VERSION 5.8 ;
BUSBITCHARS "[]" ;
DIVIDERCHAR "/" ;
UNITS
    DATABASE MICRONS 1000 ;
END UNITS

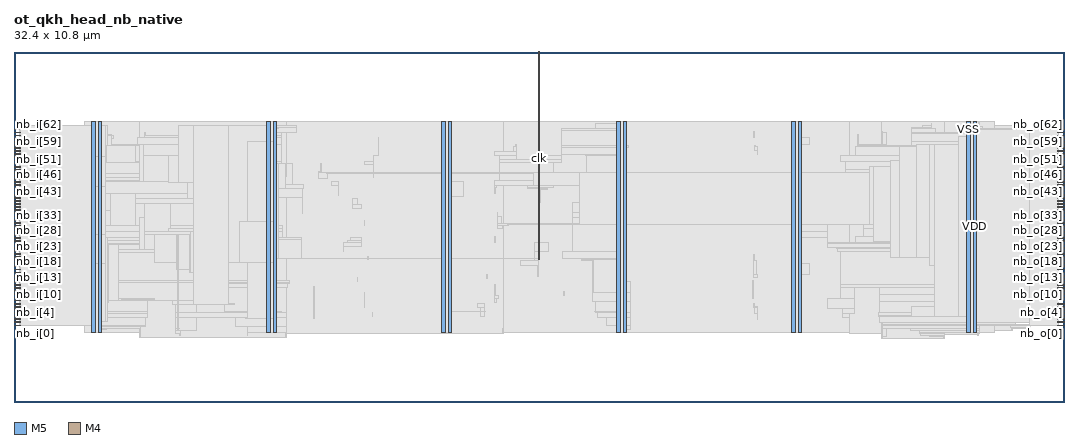
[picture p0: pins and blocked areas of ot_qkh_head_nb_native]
MACRO ot_qkh_head_nb_native
  FOREIGN ot_qkh_head_nb_native 0 0 ;
  CLASS BLOCK ;
  SIZE 32.4 BY 10.8 ;
  PIN clk
    DIRECTION INPUT ;
    USE SIGNAL ;
    PORT
      LAYER M5 ;
        RECT  16.176 10.608 16.2 10.8 ;
    END
    PORT
      LAYER M5 ;
        RECT  16.176 4.405 16.2 10.64 ;
    END
  END clk
  PIN nb_i[0]
    DIRECTION INPUT ;
    USE SIGNAL ;
    PORT
      LAYER M4 ;
        RECT  0 2.352 0.192 2.376 ;
    END
  END nb_i[0]
  PIN nb_i[10]
    DIRECTION INPUT ;
    USE SIGNAL ;
    PORT
      LAYER M4 ;
        RECT  0 3.312 0.192 3.336 ;
    END
  END nb_i[10]
  PIN nb_i[11]
    DIRECTION INPUT ;
    USE SIGNAL ;
    PORT
      LAYER M4 ;
        RECT  0 3.408 0.192 3.432 ;
    END
  END nb_i[11]
  PIN nb_i[12]
    DIRECTION INPUT ;
    USE SIGNAL ;
    PORT
      LAYER M4 ;
        RECT  0 3.504 0.192 3.528 ;
    END
  END nb_i[12]
  PIN nb_i[13]
    DIRECTION INPUT ;
    USE SIGNAL ;
    PORT
      LAYER M4 ;
        RECT  0 3.6 0.192 3.624 ;
    END
  END nb_i[13]
  PIN nb_i[14]
    DIRECTION INPUT ;
    USE SIGNAL ;
    PORT
      LAYER M4 ;
        RECT  0 3.696 0.192 3.72 ;
    END
  END nb_i[14]
  PIN nb_i[15]
    DIRECTION INPUT ;
    USE SIGNAL ;
    PORT
      LAYER M4 ;
        RECT  0 3.792 0.192 3.816 ;
    END
  END nb_i[15]
  PIN nb_i[16]
    DIRECTION INPUT ;
    USE SIGNAL ;
    PORT
      LAYER M4 ;
        RECT  0 3.888 0.192 3.912 ;
    END
  END nb_i[16]
  PIN nb_i[17]
    DIRECTION INPUT ;
    USE SIGNAL ;
    PORT
      LAYER M4 ;
        RECT  0 3.984 0.192 4.008 ;
    END
  END nb_i[17]
  PIN nb_i[18]
    DIRECTION INPUT ;
    USE SIGNAL ;
    PORT
      LAYER M4 ;
        RECT  0 4.08 0.192 4.104 ;
    END
  END nb_i[18]
  PIN nb_i[19]
    DIRECTION INPUT ;
    USE SIGNAL ;
    PORT
      LAYER M4 ;
        RECT  0 4.176 0.192 4.2 ;
    END
  END nb_i[19]
  PIN nb_i[1]
    DIRECTION INPUT ;
    USE SIGNAL ;
    PORT
      LAYER M4 ;
        RECT  0 2.448 0.192 2.472 ;
    END
  END nb_i[1]
  PIN nb_i[20]
    DIRECTION INPUT ;
    USE SIGNAL ;
    PORT
      LAYER M4 ;
        RECT  0 4.272 0.192 4.296 ;
    END
  END nb_i[20]
  PIN nb_i[21]
    DIRECTION INPUT ;
    USE SIGNAL ;
    PORT
      LAYER M4 ;
        RECT  0 4.368 0.192 4.392 ;
    END
  END nb_i[21]
  PIN nb_i[22]
    DIRECTION INPUT ;
    USE SIGNAL ;
    PORT
      LAYER M4 ;
        RECT  0 4.464 0.192 4.488 ;
    END
  END nb_i[22]
  PIN nb_i[23]
    DIRECTION INPUT ;
    USE SIGNAL ;
    PORT
      LAYER M4 ;
        RECT  0 4.56 0.192 4.584 ;
    END
  END nb_i[23]
  PIN nb_i[24]
    DIRECTION INPUT ;
    USE SIGNAL ;
    PORT
      LAYER M4 ;
        RECT  0 4.656 0.192 4.68 ;
    END
  END nb_i[24]
  PIN nb_i[25]
    DIRECTION INPUT ;
    USE SIGNAL ;
    PORT
      LAYER M4 ;
        RECT  0 4.752 0.192 4.776 ;
    END
  END nb_i[25]
  PIN nb_i[26]
    DIRECTION INPUT ;
    USE SIGNAL ;
    PORT
      LAYER M4 ;
        RECT  0 4.848 0.192 4.872 ;
    END
  END nb_i[26]
  PIN nb_i[27]
    DIRECTION INPUT ;
    USE SIGNAL ;
    PORT
      LAYER M4 ;
        RECT  0 4.944 0.192 4.968 ;
    END
  END nb_i[27]
  PIN nb_i[28]
    DIRECTION INPUT ;
    USE SIGNAL ;
    PORT
      LAYER M4 ;
        RECT  0 5.04 0.192 5.064 ;
    END
  END nb_i[28]
  PIN nb_i[29]
    DIRECTION INPUT ;
    USE SIGNAL ;
    PORT
      LAYER M4 ;
        RECT  0 5.136 0.192 5.16 ;
    END
  END nb_i[29]
  PIN nb_i[2]
    DIRECTION INPUT ;
    USE SIGNAL ;
    PORT
      LAYER M4 ;
        RECT  0 2.544 0.192 2.568 ;
    END
  END nb_i[2]
  PIN nb_i[30]
    DIRECTION INPUT ;
    USE SIGNAL ;
    PORT
      LAYER M4 ;
        RECT  0 5.232 0.192 5.256 ;
    END
  END nb_i[30]
  PIN nb_i[31]
    DIRECTION INPUT ;
    USE SIGNAL ;
    PORT
      LAYER M4 ;
        RECT  0 5.328 0.192 5.352 ;
    END
  END nb_i[31]
  PIN nb_i[32]
    DIRECTION INPUT ;
    USE SIGNAL ;
    PORT
      LAYER M4 ;
        RECT  0 5.424 0.192 5.448 ;
    END
  END nb_i[32]
  PIN nb_i[33]
    DIRECTION INPUT ;
    USE SIGNAL ;
    PORT
      LAYER M4 ;
        RECT  0 5.52 0.192 5.544 ;
    END
  END nb_i[33]
  PIN nb_i[34]
    DIRECTION INPUT ;
    USE SIGNAL ;
    PORT
      LAYER M4 ;
        RECT  0 5.616 0.192 5.64 ;
    END
  END nb_i[34]
  PIN nb_i[35]
    DIRECTION INPUT ;
    USE SIGNAL ;
    PORT
      LAYER M4 ;
        RECT  0 5.712 0.192 5.736 ;
    END
  END nb_i[35]
  PIN nb_i[36]
    DIRECTION INPUT ;
    USE SIGNAL ;
    PORT
      LAYER M4 ;
        RECT  0 5.808 0.192 5.832 ;
    END
  END nb_i[36]
  PIN nb_i[37]
    DIRECTION INPUT ;
    USE SIGNAL ;
    PORT
      LAYER M4 ;
        RECT  0 5.904 0.192 5.928 ;
    END
  END nb_i[37]
  PIN nb_i[38]
    DIRECTION INPUT ;
    USE SIGNAL ;
    PORT
      LAYER M4 ;
        RECT  0 6 0.192 6.024 ;
    END
  END nb_i[38]
  PIN nb_i[39]
    DIRECTION INPUT ;
    USE SIGNAL ;
    PORT
      LAYER M4 ;
        RECT  0 6.096 0.192 6.12 ;
    END
  END nb_i[39]
  PIN nb_i[3]
    DIRECTION INPUT ;
    USE SIGNAL ;
    PORT
      LAYER M4 ;
        RECT  0 2.64 0.192 2.664 ;
    END
  END nb_i[3]
  PIN nb_i[40]
    DIRECTION INPUT ;
    USE SIGNAL ;
    PORT
      LAYER M4 ;
        RECT  0 6.192 0.192 6.216 ;
    END
  END nb_i[40]
  PIN nb_i[41]
    DIRECTION INPUT ;
    USE SIGNAL ;
    PORT
      LAYER M4 ;
        RECT  0 6.288 0.192 6.312 ;
    END
  END nb_i[41]
  PIN nb_i[42]
    DIRECTION INPUT ;
    USE SIGNAL ;
    PORT
      LAYER M4 ;
        RECT  0 6.384 0.192 6.408 ;
    END
  END nb_i[42]
  PIN nb_i[43]
    DIRECTION INPUT ;
    USE SIGNAL ;
    PORT
      LAYER M4 ;
        RECT  0 6.48 0.192 6.504 ;
    END
  END nb_i[43]
  PIN nb_i[44]
    DIRECTION INPUT ;
    USE SIGNAL ;
    PORT
      LAYER M4 ;
        RECT  0 6.576 0.192 6.6 ;
    END
  END nb_i[44]
  PIN nb_i[45]
    DIRECTION INPUT ;
    USE SIGNAL ;
    PORT
      LAYER M4 ;
        RECT  0 6.672 0.192 6.696 ;
    END
  END nb_i[45]
  PIN nb_i[46]
    DIRECTION INPUT ;
    USE SIGNAL ;
    PORT
      LAYER M4 ;
        RECT  0 6.768 0.192 6.792 ;
    END
  END nb_i[46]
  PIN nb_i[47]
    DIRECTION INPUT ;
    USE SIGNAL ;
    PORT
      LAYER M4 ;
        RECT  0 6.864 0.192 6.888 ;
    END
  END nb_i[47]
  PIN nb_i[48]
    DIRECTION INPUT ;
    USE SIGNAL ;
    PORT
      LAYER M4 ;
        RECT  0 6.96 0.192 6.984 ;
    END
  END nb_i[48]
  PIN nb_i[49]
    DIRECTION INPUT ;
    USE SIGNAL ;
    PORT
      LAYER M4 ;
        RECT  0 7.056 0.192 7.08 ;
    END
  END nb_i[49]
  PIN nb_i[4]
    DIRECTION INPUT ;
    USE SIGNAL ;
    PORT
      LAYER M4 ;
        RECT  0 2.736 0.192 2.76 ;
    END
  END nb_i[4]
  PIN nb_i[50]
    DIRECTION INPUT ;
    USE SIGNAL ;
    PORT
      LAYER M4 ;
        RECT  0 7.152 0.192 7.176 ;
    END
  END nb_i[50]
  PIN nb_i[51]
    DIRECTION INPUT ;
    USE SIGNAL ;
    PORT
      LAYER M4 ;
        RECT  0 7.248 0.192 7.272 ;
    END
  END nb_i[51]
  PIN nb_i[52]
    DIRECTION INPUT ;
    USE SIGNAL ;
    PORT
      LAYER M4 ;
        RECT  0 7.344 0.192 7.368 ;
    END
  END nb_i[52]
  PIN nb_i[53]
    DIRECTION INPUT ;
    USE SIGNAL ;
    PORT
      LAYER M4 ;
        RECT  0 7.44 0.192 7.464 ;
    END
  END nb_i[53]
  PIN nb_i[54]
    DIRECTION INPUT ;
    USE SIGNAL ;
    PORT
      LAYER M4 ;
        RECT  0 7.536 0.192 7.56 ;
    END
  END nb_i[54]
  PIN nb_i[55]
    DIRECTION INPUT ;
    USE SIGNAL ;
    PORT
      LAYER M4 ;
        RECT  0 7.632 0.192 7.656 ;
    END
  END nb_i[55]
  PIN nb_i[56]
    DIRECTION INPUT ;
    USE SIGNAL ;
    PORT
      LAYER M4 ;
        RECT  0 7.728 0.192 7.752 ;
    END
  END nb_i[56]
  PIN nb_i[57]
    DIRECTION INPUT ;
    USE SIGNAL ;
    PORT
      LAYER M4 ;
        RECT  0 7.824 0.192 7.848 ;
    END
  END nb_i[57]
  PIN nb_i[58]
    DIRECTION INPUT ;
    USE SIGNAL ;
    PORT
      LAYER M4 ;
        RECT  0 7.92 0.192 7.944 ;
    END
  END nb_i[58]
  PIN nb_i[59]
    DIRECTION INPUT ;
    USE SIGNAL ;
    PORT
      LAYER M4 ;
        RECT  0 8.016 0.192 8.04 ;
    END
  END nb_i[59]
  PIN nb_i[5]
    DIRECTION INPUT ;
    USE SIGNAL ;
    PORT
      LAYER M4 ;
        RECT  0 2.832 0.192 2.856 ;
    END
  END nb_i[5]
  PIN nb_i[60]
    DIRECTION INPUT ;
    USE SIGNAL ;
    PORT
      LAYER M4 ;
        RECT  0 8.112 0.192 8.136 ;
    END
  END nb_i[60]
  PIN nb_i[61]
    DIRECTION INPUT ;
    USE SIGNAL ;
    PORT
      LAYER M4 ;
        RECT  0 8.208 0.192 8.232 ;
    END
  END nb_i[61]
  PIN nb_i[62]
    DIRECTION INPUT ;
    USE SIGNAL ;
    PORT
      LAYER M4 ;
        RECT  0 8.304 0.192 8.328 ;
    END
  END nb_i[62]
  PIN nb_i[63]
    DIRECTION INPUT ;
    USE SIGNAL ;
    PORT
      LAYER M4 ;
        RECT  0 8.4 0.192 8.424 ;
    END
  END nb_i[63]
  PIN nb_i[6]
    DIRECTION INPUT ;
    USE SIGNAL ;
    PORT
      LAYER M4 ;
        RECT  0 2.928 0.192 2.952 ;
    END
  END nb_i[6]
  PIN nb_i[7]
    DIRECTION INPUT ;
    USE SIGNAL ;
    PORT
      LAYER M4 ;
        RECT  0 3.024 0.192 3.048 ;
    END
  END nb_i[7]
  PIN nb_i[8]
    DIRECTION INPUT ;
    USE SIGNAL ;
    PORT
      LAYER M4 ;
        RECT  0 3.12 0.192 3.144 ;
    END
  END nb_i[8]
  PIN nb_i[9]
    DIRECTION INPUT ;
    USE SIGNAL ;
    PORT
      LAYER M4 ;
        RECT  0 3.216 0.192 3.24 ;
    END
  END nb_i[9]
  PIN nb_o[0]
    DIRECTION OUTPUT ;
    USE SIGNAL ;
    PORT
      LAYER M4 ;
        RECT  32.208 2.352 32.4 2.376 ;
    END
  END nb_o[0]
  PIN nb_o[10]
    DIRECTION OUTPUT ;
    USE SIGNAL ;
    PORT
      LAYER M4 ;
        RECT  32.208 3.312 32.4 3.336 ;
    END
  END nb_o[10]
  PIN nb_o[11]
    DIRECTION OUTPUT ;
    USE SIGNAL ;
    PORT
      LAYER M4 ;
        RECT  32.208 3.408 32.4 3.432 ;
    END
  END nb_o[11]
  PIN nb_o[12]
    DIRECTION OUTPUT ;
    USE SIGNAL ;
    PORT
      LAYER M4 ;
        RECT  32.208 3.504 32.4 3.528 ;
    END
  END nb_o[12]
  PIN nb_o[13]
    DIRECTION OUTPUT ;
    USE SIGNAL ;
    PORT
      LAYER M4 ;
        RECT  32.208 3.6 32.4 3.624 ;
    END
  END nb_o[13]
  PIN nb_o[14]
    DIRECTION OUTPUT ;
    USE SIGNAL ;
    PORT
      LAYER M4 ;
        RECT  32.208 3.696 32.4 3.72 ;
    END
  END nb_o[14]
  PIN nb_o[15]
    DIRECTION OUTPUT ;
    USE SIGNAL ;
    PORT
      LAYER M4 ;
        RECT  32.208 3.792 32.4 3.816 ;
    END
  END nb_o[15]
  PIN nb_o[16]
    DIRECTION OUTPUT ;
    USE SIGNAL ;
    PORT
      LAYER M4 ;
        RECT  32.208 3.888 32.4 3.912 ;
    END
  END nb_o[16]
  PIN nb_o[17]
    DIRECTION OUTPUT ;
    USE SIGNAL ;
    PORT
      LAYER M4 ;
        RECT  32.208 3.984 32.4 4.008 ;
    END
  END nb_o[17]
  PIN nb_o[18]
    DIRECTION OUTPUT ;
    USE SIGNAL ;
    PORT
      LAYER M4 ;
        RECT  32.208 4.08 32.4 4.104 ;
    END
  END nb_o[18]
  PIN nb_o[19]
    DIRECTION OUTPUT ;
    USE SIGNAL ;
    PORT
      LAYER M4 ;
        RECT  32.208 4.176 32.4 4.2 ;
    END
  END nb_o[19]
  PIN nb_o[1]
    DIRECTION OUTPUT ;
    USE SIGNAL ;
    PORT
      LAYER M4 ;
        RECT  32.208 2.448 32.4 2.472 ;
    END
  END nb_o[1]
  PIN nb_o[20]
    DIRECTION OUTPUT ;
    USE SIGNAL ;
    PORT
      LAYER M4 ;
        RECT  32.208 4.272 32.4 4.296 ;
    END
  END nb_o[20]
  PIN nb_o[21]
    DIRECTION OUTPUT ;
    USE SIGNAL ;
    PORT
      LAYER M4 ;
        RECT  32.208 4.368 32.4 4.392 ;
    END
  END nb_o[21]
  PIN nb_o[22]
    DIRECTION OUTPUT ;
    USE SIGNAL ;
    PORT
      LAYER M4 ;
        RECT  32.208 4.464 32.4 4.488 ;
    END
  END nb_o[22]
  PIN nb_o[23]
    DIRECTION OUTPUT ;
    USE SIGNAL ;
    PORT
      LAYER M4 ;
        RECT  32.208 4.56 32.4 4.584 ;
    END
  END nb_o[23]
  PIN nb_o[24]
    DIRECTION OUTPUT ;
    USE SIGNAL ;
    PORT
      LAYER M4 ;
        RECT  32.208 4.656 32.4 4.68 ;
    END
  END nb_o[24]
  PIN nb_o[25]
    DIRECTION OUTPUT ;
    USE SIGNAL ;
    PORT
      LAYER M4 ;
        RECT  32.208 4.752 32.4 4.776 ;
    END
  END nb_o[25]
  PIN nb_o[26]
    DIRECTION OUTPUT ;
    USE SIGNAL ;
    PORT
      LAYER M4 ;
        RECT  32.208 4.848 32.4 4.872 ;
    END
  END nb_o[26]
  PIN nb_o[27]
    DIRECTION OUTPUT ;
    USE SIGNAL ;
    PORT
      LAYER M4 ;
        RECT  32.208 4.944 32.4 4.968 ;
    END
  END nb_o[27]
  PIN nb_o[28]
    DIRECTION OUTPUT ;
    USE SIGNAL ;
    PORT
      LAYER M4 ;
        RECT  32.208 5.04 32.4 5.064 ;
    END
  END nb_o[28]
  PIN nb_o[29]
    DIRECTION OUTPUT ;
    USE SIGNAL ;
    PORT
      LAYER M4 ;
        RECT  32.208 5.136 32.4 5.16 ;
    END
  END nb_o[29]
  PIN nb_o[2]
    DIRECTION OUTPUT ;
    USE SIGNAL ;
    PORT
      LAYER M4 ;
        RECT  32.208 2.544 32.4 2.568 ;
    END
  END nb_o[2]
  PIN nb_o[30]
    DIRECTION OUTPUT ;
    USE SIGNAL ;
    PORT
      LAYER M4 ;
        RECT  32.208 5.232 32.4 5.256 ;
    END
  END nb_o[30]
  PIN nb_o[31]
    DIRECTION OUTPUT ;
    USE SIGNAL ;
    PORT
      LAYER M4 ;
        RECT  32.208 5.328 32.4 5.352 ;
    END
  END nb_o[31]
  PIN nb_o[32]
    DIRECTION OUTPUT ;
    USE SIGNAL ;
    PORT
      LAYER M4 ;
        RECT  32.208 5.424 32.4 5.448 ;
    END
  END nb_o[32]
  PIN nb_o[33]
    DIRECTION OUTPUT ;
    USE SIGNAL ;
    PORT
      LAYER M4 ;
        RECT  32.208 5.52 32.4 5.544 ;
    END
  END nb_o[33]
  PIN nb_o[34]
    DIRECTION OUTPUT ;
    USE SIGNAL ;
    PORT
      LAYER M4 ;
        RECT  32.208 5.616 32.4 5.64 ;
    END
  END nb_o[34]
  PIN nb_o[35]
    DIRECTION OUTPUT ;
    USE SIGNAL ;
    PORT
      LAYER M4 ;
        RECT  32.208 5.712 32.4 5.736 ;
    END
  END nb_o[35]
  PIN nb_o[36]
    DIRECTION OUTPUT ;
    USE SIGNAL ;
    PORT
      LAYER M4 ;
        RECT  32.208 5.808 32.4 5.832 ;
    END
  END nb_o[36]
  PIN nb_o[37]
    DIRECTION OUTPUT ;
    USE SIGNAL ;
    PORT
      LAYER M4 ;
        RECT  32.208 5.904 32.4 5.928 ;
    END
  END nb_o[37]
  PIN nb_o[38]
    DIRECTION OUTPUT ;
    USE SIGNAL ;
    PORT
      LAYER M4 ;
        RECT  32.208 6 32.4 6.024 ;
    END
  END nb_o[38]
  PIN nb_o[39]
    DIRECTION OUTPUT ;
    USE SIGNAL ;
    PORT
      LAYER M4 ;
        RECT  32.208 6.096 32.4 6.12 ;
    END
  END nb_o[39]
  PIN nb_o[3]
    DIRECTION OUTPUT ;
    USE SIGNAL ;
    PORT
      LAYER M4 ;
        RECT  32.208 2.64 32.4 2.664 ;
    END
  END nb_o[3]
  PIN nb_o[40]
    DIRECTION OUTPUT ;
    USE SIGNAL ;
    PORT
      LAYER M4 ;
        RECT  32.208 6.192 32.4 6.216 ;
    END
  END nb_o[40]
  PIN nb_o[41]
    DIRECTION OUTPUT ;
    USE SIGNAL ;
    PORT
      LAYER M4 ;
        RECT  32.208 6.288 32.4 6.312 ;
    END
  END nb_o[41]
  PIN nb_o[42]
    DIRECTION OUTPUT ;
    USE SIGNAL ;
    PORT
      LAYER M4 ;
        RECT  32.208 6.384 32.4 6.408 ;
    END
  END nb_o[42]
  PIN nb_o[43]
    DIRECTION OUTPUT ;
    USE SIGNAL ;
    PORT
      LAYER M4 ;
        RECT  32.208 6.48 32.4 6.504 ;
    END
  END nb_o[43]
  PIN nb_o[44]
    DIRECTION OUTPUT ;
    USE SIGNAL ;
    PORT
      LAYER M4 ;
        RECT  32.208 6.576 32.4 6.6 ;
    END
  END nb_o[44]
  PIN nb_o[45]
    DIRECTION OUTPUT ;
    USE SIGNAL ;
    PORT
      LAYER M4 ;
        RECT  32.208 6.672 32.4 6.696 ;
    END
  END nb_o[45]
  PIN nb_o[46]
    DIRECTION OUTPUT ;
    USE SIGNAL ;
    PORT
      LAYER M4 ;
        RECT  32.208 6.768 32.4 6.792 ;
    END
  END nb_o[46]
  PIN nb_o[47]
    DIRECTION OUTPUT ;
    USE SIGNAL ;
    PORT
      LAYER M4 ;
        RECT  32.208 6.864 32.4 6.888 ;
    END
  END nb_o[47]
  PIN nb_o[48]
    DIRECTION OUTPUT ;
    USE SIGNAL ;
    PORT
      LAYER M4 ;
        RECT  32.208 6.96 32.4 6.984 ;
    END
  END nb_o[48]
  PIN nb_o[49]
    DIRECTION OUTPUT ;
    USE SIGNAL ;
    PORT
      LAYER M4 ;
        RECT  32.208 7.056 32.4 7.08 ;
    END
  END nb_o[49]
  PIN nb_o[4]
    DIRECTION OUTPUT ;
    USE SIGNAL ;
    PORT
      LAYER M4 ;
        RECT  32.208 2.736 32.4 2.76 ;
    END
  END nb_o[4]
  PIN nb_o[50]
    DIRECTION OUTPUT ;
    USE SIGNAL ;
    PORT
      LAYER M4 ;
        RECT  32.208 7.152 32.4 7.176 ;
    END
  END nb_o[50]
  PIN nb_o[51]
    DIRECTION OUTPUT ;
    USE SIGNAL ;
    PORT
      LAYER M4 ;
        RECT  32.208 7.248 32.4 7.272 ;
    END
  END nb_o[51]
  PIN nb_o[52]
    DIRECTION OUTPUT ;
    USE SIGNAL ;
    PORT
      LAYER M4 ;
        RECT  32.208 7.344 32.4 7.368 ;
    END
  END nb_o[52]
  PIN nb_o[53]
    DIRECTION OUTPUT ;
    USE SIGNAL ;
    PORT
      LAYER M4 ;
        RECT  32.208 7.44 32.4 7.464 ;
    END
  END nb_o[53]
  PIN nb_o[54]
    DIRECTION OUTPUT ;
    USE SIGNAL ;
    PORT
      LAYER M4 ;
        RECT  32.208 7.536 32.4 7.56 ;
    END
  END nb_o[54]
  PIN nb_o[55]
    DIRECTION OUTPUT ;
    USE SIGNAL ;
    PORT
      LAYER M4 ;
        RECT  32.208 7.632 32.4 7.656 ;
    END
  END nb_o[55]
  PIN nb_o[56]
    DIRECTION OUTPUT ;
    USE SIGNAL ;
    PORT
      LAYER M4 ;
        RECT  32.208 7.728 32.4 7.752 ;
    END
  END nb_o[56]
  PIN nb_o[57]
    DIRECTION OUTPUT ;
    USE SIGNAL ;
    PORT
      LAYER M4 ;
        RECT  32.208 7.824 32.4 7.848 ;
    END
  END nb_o[57]
  PIN nb_o[58]
    DIRECTION OUTPUT ;
    USE SIGNAL ;
    PORT
      LAYER M4 ;
        RECT  32.208 7.92 32.4 7.944 ;
    END
  END nb_o[58]
  PIN nb_o[59]
    DIRECTION OUTPUT ;
    USE SIGNAL ;
    PORT
      LAYER M4 ;
        RECT  32.208 8.016 32.4 8.04 ;
    END
  END nb_o[59]
  PIN nb_o[5]
    DIRECTION OUTPUT ;
    USE SIGNAL ;
    PORT
      LAYER M4 ;
        RECT  32.208 2.832 32.4 2.856 ;
    END
  END nb_o[5]
  PIN nb_o[60]
    DIRECTION OUTPUT ;
    USE SIGNAL ;
    PORT
      LAYER M4 ;
        RECT  32.208 8.112 32.4 8.136 ;
    END
  END nb_o[60]
  PIN nb_o[61]
    DIRECTION OUTPUT ;
    USE SIGNAL ;
    PORT
      LAYER M4 ;
        RECT  32.208 8.208 32.4 8.232 ;
    END
  END nb_o[61]
  PIN nb_o[62]
    DIRECTION OUTPUT ;
    USE SIGNAL ;
    PORT
      LAYER M4 ;
        RECT  32.208 8.304 32.4 8.328 ;
    END
  END nb_o[62]
  PIN nb_o[63]
    DIRECTION OUTPUT ;
    USE SIGNAL ;
    PORT
      LAYER M4 ;
        RECT  32.208 8.4 32.4 8.424 ;
    END
  END nb_o[63]
  PIN nb_o[6]
    DIRECTION OUTPUT ;
    USE SIGNAL ;
    PORT
      LAYER M4 ;
        RECT  32.208 2.928 32.4 2.952 ;
    END
  END nb_o[6]
  PIN nb_o[7]
    DIRECTION OUTPUT ;
    USE SIGNAL ;
    PORT
      LAYER M4 ;
        RECT  32.208 3.024 32.4 3.048 ;
    END
  END nb_o[7]
  PIN nb_o[8]
    DIRECTION OUTPUT ;
    USE SIGNAL ;
    PORT
      LAYER M4 ;
        RECT  32.208 3.12 32.4 3.144 ;
    END
  END nb_o[8]
  PIN nb_o[9]
    DIRECTION OUTPUT ;
    USE SIGNAL ;
    PORT
      LAYER M4 ;
        RECT  32.208 3.216 32.4 3.24 ;
    END
  END nb_o[9]
  PIN VDD
    DIRECTION INOUT ;
    USE POWER ;
    PORT
      LAYER M5 ;
        RECT  29.592 2.151 29.712 8.649 ;
        RECT  24.192 2.151 24.312 8.649 ;
        RECT  18.792 2.151 18.912 8.649 ;
        RECT  13.392 2.151 13.512 8.649 ;
        RECT  7.992 2.151 8.112 8.649 ;
        RECT  2.592 2.151 2.712 8.649 ;
    END
  END VDD
  PIN VSS
    DIRECTION INOUT ;
    USE GROUND ;
    PORT
      LAYER M5 ;
        RECT  29.4 2.137 29.52 8.663 ;
        RECT  24 2.137 24.12 8.663 ;
        RECT  18.6 2.137 18.72 8.663 ;
        RECT  13.2 2.137 13.32 8.663 ;
        RECT  7.8 2.137 7.92 8.663 ;
        RECT  2.4 2.137 2.52 8.663 ;
    END
  END VSS
  # OT_OBS_CLOSED layer=M5 d_um=1.536 added=1
  OBS
    LAYER RVTN ;
     RECT  2.16 2.16 30.24 2.295 ;
     RECT  2.16 2.565 30.24 2.835 ;
     RECT  2.16 3.105 30.24 3.375 ;
     RECT  2.16 3.645 30.24 3.915 ;
     RECT  2.16 4.185 30.24 4.455 ;
     RECT  2.16 4.725 30.24 4.995 ;
     RECT  2.16 5.265 30.24 5.535 ;
     RECT  2.16 5.805 30.24 6.075 ;
     RECT  2.16 6.345 30.24 6.615 ;
     RECT  2.16 6.885 30.24 7.155 ;
     RECT  2.16 7.425 30.24 7.695 ;
     RECT  2.16 7.965 30.24 8.235 ;
     RECT  2.16 8.505 30.24 8.64 ;
    LAYER RVTP ;
     RECT  2.16 2.295 30.24 2.565 ;
     RECT  2.16 2.835 30.24 3.105 ;
     RECT  2.16 3.375 30.24 3.645 ;
     RECT  2.16 3.915 30.24 4.185 ;
     RECT  2.16 4.455 30.24 4.725 ;
     RECT  2.16 4.995 30.24 5.265 ;
     RECT  2.16 5.535 30.24 5.805 ;
     RECT  2.16 6.075 30.24 6.345 ;
     RECT  2.16 6.615 30.24 6.885 ;
     RECT  2.16 7.155 30.24 7.425 ;
     RECT  2.16 7.695 30.24 7.965 ;
     RECT  2.16 8.235 30.24 8.505 ;
    LAYER M1 ;
     RECT  2.16 2.151 30.24 8.649 ;
    LAYER M2 ;
     RECT  0.211 2.61 0.247 2.628 ;
     RECT  0.247 2.61 0.283 2.826 ;
     RECT  0.211 5.04 0.283 5.058 ;
     RECT  0.211 6.624 0.311 6.912 ;
     RECT  0.283 4.5 0.319 5.058 ;
     RECT  0.311 6.624 0.347 6.84 ;
     RECT  0.283 2.61 0.391 3.402 ;
     RECT  0.319 4.158 0.391 5.058 ;
     RECT  0.391 2.61 2.16 5.058 ;
     RECT  0.347 6.822 2.16 6.84 ;
     RECT  2.16 2.151 3.883 8.649 ;
     RECT  3.883 1.998 8.411 8.649 ;
     RECT  8.411 2.106 15.107 8.649 ;
     RECT  15.107 2.151 25.771 8.649 ;
     RECT  25.771 2.106 26.779 8.649 ;
     RECT  26.779 1.962 28.715 8.649 ;
     RECT  28.715 2.07 29.759 8.649 ;
     RECT  29.759 2.106 29.795 8.649 ;
     RECT  29.795 2.151 30.24 8.649 ;
     RECT  30.24 2.196 30.803 8.532 ;
     RECT  30.803 4.194 30.875 8.532 ;
     RECT  30.803 2.268 30.911 3.402 ;
     RECT  30.875 5.076 30.911 8.532 ;
     RECT  30.911 5.076 30.947 5.292 ;
     RECT  30.911 7.398 31.055 8.532 ;
     RECT  30.911 2.268 31.379 2.286 ;
     RECT  30.911 3.114 31.379 3.402 ;
     RECT  30.875 4.194 31.379 4.212 ;
     RECT  30.947 5.076 31.379 5.094 ;
     RECT  31.055 7.398 31.379 8.334 ;
     RECT  31.379 3.114 31.415 3.33 ;
     RECT  31.379 7.398 31.415 7.416 ;
     RECT  31.379 8.244 31.415 8.262 ;
     RECT  31.415 3.312 31.451 3.33 ;
    LAYER M3 ;
     RECT  26.784 1.957 26.802 2.029 ;
     RECT  28.692 1.957 28.71 2.029 ;
     RECT  28.26 2.029 28.71 2.065 ;
     RECT  5.112 2.065 5.13 2.101 ;
     RECT  27.972 2.065 28.71 2.101 ;
     RECT  29.736 2.065 29.754 2.101 ;
     RECT  7.2 2.065 7.218 2.143 ;
     RECT  8.388 1.993 8.406 2.143 ;
     RECT  27.936 2.101 28.71 2.143 ;
     RECT  29.736 2.101 29.79 2.143 ;
     RECT  4.968 2.101 5.13 2.191 ;
     RECT  27.936 2.143 29.79 2.191 ;
     RECT  2.415 2.143 2.505 2.227 ;
     RECT  18.615 2.143 18.705 2.227 ;
     RECT  15.084 2.101 15.102 2.255 ;
     RECT  2.415 2.227 2.862 2.263 ;
     RECT  3.888 1.993 3.906 2.263 ;
     RECT  26.784 2.029 26.91 2.263 ;
     RECT  27.648 2.191 29.79 2.263 ;
     RECT  30.78 2.191 30.798 2.263 ;
     RECT  30.78 2.263 31.374 2.299 ;
     RECT  2.415 2.263 3.906 2.335 ;
     RECT  7.2 2.143 8.406 2.335 ;
     RECT  2.415 2.335 4.05 2.347 ;
     RECT  18.615 2.227 19.026 2.371 ;
     RECT  26.784 2.263 29.79 2.371 ;
     RECT  30.744 2.299 31.374 2.371 ;
     RECT  26.784 2.371 31.374 2.381 ;
     RECT  13.215 2.143 13.305 2.413 ;
     RECT  24.015 2.143 24.105 2.413 ;
     RECT  26.784 2.381 30.906 2.461 ;
     RECT  0.252 2.491 0.27 2.605 ;
     RECT  2.304 2.347 4.05 2.605 ;
     RECT  4.968 2.191 5.634 2.605 ;
     RECT  6.84 2.335 8.406 2.605 ;
     RECT  18.288 2.371 19.026 2.605 ;
     RECT  25.776 2.101 25.794 2.605 ;
     RECT  26.712 2.461 30.906 2.635 ;
     RECT  2.304 2.605 4.122 2.731 ;
     RECT  22.932 2.533 22.95 2.731 ;
     RECT  25.56 2.605 25.794 2.731 ;
     RECT  4.968 2.605 8.406 2.759 ;
     RECT  11.052 2.641 11.07 2.759 ;
     RECT  26.676 2.635 30.906 2.759 ;
     RECT  18 2.605 19.026 2.767 ;
     RECT  2.268 2.731 4.122 2.795 ;
     RECT  6.48 2.759 8.262 2.795 ;
     RECT  25.56 2.731 25.938 2.875 ;
     RECT  14.4 2.641 14.526 2.911 ;
     RECT  22.86 2.731 22.95 2.911 ;
     RECT  22.824 2.911 22.95 2.939 ;
     RECT  4.968 2.759 5.634 3.001 ;
     RECT  14.292 2.911 14.526 3.029 ;
     RECT  22.824 2.939 22.842 3.029 ;
     RECT  0.216 2.605 0.27 3.067 ;
     RECT  17.928 2.767 19.026 3.109 ;
     RECT  26.712 2.759 30.906 3.109 ;
     RECT  2.304 2.795 4.122 3.145 ;
     RECT  4.896 3.001 5.634 3.145 ;
     RECT  14.832 3.073 14.886 3.181 ;
     RECT  25.092 2.875 25.938 3.209 ;
     RECT  14.832 3.181 14.958 3.299 ;
     RECT  26.712 3.109 31.41 3.307 ;
     RECT  0.216 3.067 0.342 3.341 ;
     RECT  10.8 2.911 10.818 3.371 ;
     RECT  17.856 3.109 19.026 3.371 ;
     RECT  16.956 3.271 16.974 3.407 ;
     RECT  6.48 2.795 8.097 3.541 ;
     RECT  25.488 3.209 25.938 3.541 ;
     RECT  26.712 3.307 31.446 3.541 ;
     RECT  9.252 2.569 9.27 3.569 ;
     RECT  25.488 3.541 31.446 3.629 ;
     RECT  14.832 3.299 14.85 3.641 ;
     RECT  6.48 3.541 8.442 3.649 ;
     RECT  2.304 3.145 5.634 3.685 ;
     RECT  2.304 3.685 5.706 3.691 ;
     RECT  6.48 3.649 8.514 3.691 ;
     RECT  18.615 3.371 19.026 3.713 ;
     RECT  2.304 3.691 8.514 3.749 ;
     RECT  22.788 3.181 22.806 3.749 ;
     RECT  0.288 3.341 0.342 3.787 ;
     RECT  10.584 3.721 10.602 3.839 ;
     RECT  0.288 3.787 0.45 3.847 ;
     RECT  24.015 2.413 24.297 3.919 ;
     RECT  14.58 3.811 14.598 3.947 ;
     RECT  22.824 3.847 22.95 3.947 ;
     RECT  0.288 3.847 0.558 4.109 ;
     RECT  16.164 3.883 16.182 4.225 ;
     RECT  24.015 3.919 24.534 4.289 ;
     RECT  17.856 3.371 17.874 4.351 ;
     RECT  15.624 4.225 16.182 4.379 ;
     RECT  22.824 3.947 22.914 4.379 ;
     RECT  17.496 4.351 17.874 4.387 ;
     RECT  18.615 3.713 18.897 4.387 ;
     RECT  17.496 4.387 18.897 4.423 ;
     RECT  10.908 4.387 10.926 4.487 ;
     RECT  0.288 4.109 0.342 4.555 ;
     RECT  22.824 4.379 22.842 4.559 ;
     RECT  2.304 3.749 8.097 4.621 ;
     RECT  16.92 4.423 18.897 4.649 ;
     RECT  16.056 4.379 16.182 4.657 ;
     RECT  25.488 3.629 31.374 4.657 ;
     RECT  2.304 4.621 8.19 4.729 ;
     RECT  25.416 4.657 31.374 4.729 ;
     RECT  25.38 4.729 31.374 4.765 ;
     RECT  10.152 4.657 10.17 4.801 ;
     RECT  2.268 4.729 8.19 4.877 ;
     RECT  25.092 4.765 31.374 4.877 ;
     RECT  10.152 4.801 10.71 4.919 ;
     RECT  16.056 4.657 16.506 4.919 ;
     RECT  25.092 4.877 30.042 4.919 ;
     RECT  0.252 4.555 0.342 4.963 ;
     RECT  2.304 4.877 8.19 4.987 ;
     RECT  10.296 4.919 10.71 4.991 ;
     RECT  0.252 4.963 0.558 5.035 ;
     RECT  2.304 4.987 8.874 5.063 ;
     RECT  10.368 4.991 10.71 5.063 ;
     RECT  24.015 4.289 24.297 5.071 ;
     RECT  25.092 4.919 25.11 5.071 ;
     RECT  14.832 4.927 14.85 5.099 ;
     RECT  25.956 4.919 30.042 5.099 ;
     RECT  30.78 4.877 31.374 5.099 ;
     RECT  0.216 5.035 0.558 5.165 ;
     RECT  0.288 5.165 0.558 5.261 ;
     RECT  2.304 5.063 8.298 5.261 ;
     RECT  24.015 5.071 25.11 5.261 ;
     RECT  0.288 5.261 0.342 5.357 ;
     RECT  26.208 5.099 30.042 5.357 ;
     RECT  4.752 5.261 8.298 5.369 ;
     RECT  14.904 5.341 15.066 5.431 ;
     RECT  0.324 5.357 0.342 5.453 ;
     RECT  2.304 5.261 4.014 5.459 ;
     RECT  4.824 5.369 8.298 5.459 ;
     RECT  14.904 5.431 15.246 5.501 ;
     RECT  10.8 5.431 10.818 5.603 ;
     RECT  30.78 5.099 30.942 5.645 ;
     RECT  25.092 5.261 25.11 5.693 ;
     RECT  17.244 4.649 18.897 5.707 ;
     RECT  14.904 5.501 15.03 5.729 ;
     RECT  14.904 5.729 14.922 5.837 ;
     RECT  17.244 5.707 18.99 5.837 ;
     RECT  26.208 5.357 29.97 5.881 ;
     RECT  2.304 5.459 2.97 5.899 ;
     RECT  25.308 5.881 29.97 5.999 ;
     RECT  25.668 5.999 29.97 6.079 ;
     RECT  30.78 5.645 30.906 6.079 ;
     RECT  10.44 5.971 10.71 6.107 ;
     RECT  3.744 5.459 4.014 6.115 ;
     RECT  4.824 5.459 8.154 6.115 ;
     RECT  17.244 5.837 18.897 6.143 ;
     RECT  3.744 6.115 8.154 6.269 ;
     RECT  10.44 6.107 10.602 6.269 ;
     RECT  6.408 6.269 8.154 6.313 ;
     RECT  8.892 5.809 8.91 6.313 ;
     RECT  13.215 2.413 13.497 6.349 ;
     RECT  2.268 5.899 2.97 6.421 ;
     RECT  3.744 6.269 5.346 6.421 ;
     RECT  16.236 6.151 16.254 6.547 ;
     RECT  0.396 6.475 0.414 6.571 ;
     RECT  6.408 6.313 8.91 6.583 ;
     RECT  16.236 6.547 16.47 6.583 ;
     RECT  0.216 6.571 0.414 6.605 ;
     RECT  14.832 6.421 14.85 6.619 ;
     RECT  15.84 6.583 16.47 6.619 ;
     RECT  22.824 6.007 22.842 6.619 ;
     RECT  22.824 6.619 22.914 6.647 ;
     RECT  0.216 6.605 0.342 6.656 ;
     RECT  10.008 6.385 10.026 6.691 ;
     RECT  14.832 6.619 14.886 6.691 ;
     RECT  15.84 6.619 16.65 6.691 ;
     RECT  6.408 6.583 8.946 6.719 ;
     RECT  25.668 6.079 30.906 6.763 ;
     RECT  9.792 6.691 10.026 6.809 ;
     RECT  13.215 6.349 13.878 6.809 ;
     RECT  2.268 6.421 5.346 6.817 ;
     RECT  14.832 6.691 16.65 6.845 ;
     RECT  22.896 6.647 22.914 6.845 ;
     RECT  0.216 6.656 0.306 6.917 ;
     RECT  2.232 6.817 5.346 6.917 ;
     RECT  2.268 6.917 5.346 7.051 ;
     RECT  13.215 6.809 13.497 7.051 ;
     RECT  24.015 5.261 24.297 7.051 ;
     RECT  25.668 6.763 31.05 7.051 ;
     RECT  9.396 6.889 9.666 7.088 ;
     RECT  13.104 7.051 13.497 7.088 ;
     RECT  23.904 7.051 24.297 7.088 ;
     RECT  9.396 7.088 9.486 7.115 ;
     RECT  25.668 7.051 31.374 7.187 ;
     RECT  11.088 6.925 11.106 7.321 ;
     RECT  9.468 7.115 9.486 7.349 ;
     RECT  6.408 6.719 8.586 7.373 ;
     RECT  2.268 7.051 5.598 7.384 ;
     RECT  2.268 7.384 5.634 7.385 ;
     RECT  14.976 6.845 16.65 7.393 ;
     RECT  30.78 7.187 31.374 7.393 ;
     RECT  10.8 7.321 11.106 7.421 ;
     RECT  3.744 7.385 5.634 7.429 ;
     RECT  6.408 7.373 8.262 7.429 ;
     RECT  25.668 7.187 29.934 7.429 ;
     RECT  14.976 7.393 16.902 7.493 ;
     RECT  2.268 7.385 2.862 7.565 ;
     RECT  11.088 7.421 11.106 7.591 ;
     RECT  14.976 7.493 15.498 7.591 ;
     RECT  17.676 6.143 18.897 7.591 ;
     RECT  11.088 7.591 11.25 7.619 ;
     RECT  16.236 7.493 16.902 7.619 ;
     RECT  25.488 7.429 29.934 7.619 ;
     RECT  16.884 7.619 16.902 7.627 ;
     RECT  17.64 7.591 18.897 7.627 ;
     RECT  14.832 7.591 15.498 7.727 ;
     RECT  22.932 7.627 22.95 7.771 ;
     RECT  16.884 7.627 18.897 7.861 ;
     RECT  15.408 7.727 15.498 7.889 ;
     RECT  22.86 7.771 22.95 7.889 ;
     RECT  25.956 7.619 29.934 7.889 ;
     RECT  26.028 7.889 29.934 7.901 ;
     RECT  16.884 7.861 18.954 7.925 ;
     RECT  22.86 7.889 22.878 7.925 ;
     RECT  24.015 7.088 24.297 7.933 ;
     RECT  3.744 7.429 8.262 7.961 ;
     RECT  15.48 7.889 15.498 7.961 ;
     RECT  26.028 7.901 26.91 7.961 ;
     RECT  27.684 7.901 29.934 8.041 ;
     RECT  2.304 7.565 2.862 8.131 ;
     RECT  3.816 7.961 8.262 8.159 ;
     RECT  11.232 7.619 11.25 8.159 ;
     RECT  24.015 7.933 24.534 8.159 ;
     RECT  0.396 8.107 0.414 8.203 ;
     RECT  2.304 8.131 3.078 8.231 ;
     RECT  4.032 8.159 8.262 8.231 ;
     RECT  0.216 8.203 0.414 8.237 ;
     RECT  2.304 8.231 3.006 8.24 ;
     RECT  26.028 7.961 26.046 8.267 ;
     RECT  30.78 7.393 31.41 8.267 ;
     RECT  27.684 8.041 30.006 8.275 ;
     RECT  30.78 8.267 31.374 8.275 ;
     RECT  4.032 8.231 4.05 8.303 ;
     RECT  26.784 7.961 26.91 8.303 ;
     RECT  27.684 8.275 31.374 8.303 ;
     RECT  5.076 8.231 8.262 8.311 ;
     RECT  22.824 8.167 22.842 8.339 ;
     RECT  26.784 8.303 26.802 8.339 ;
     RECT  29.16 8.303 31.374 8.339 ;
     RECT  13.215 7.088 13.497 8.387 ;
     RECT  16.884 7.925 18.897 8.387 ;
     RECT  24.015 8.159 24.297 8.387 ;
     RECT  16.884 8.387 18.705 8.429 ;
     RECT  27.684 8.303 28.422 8.429 ;
     RECT  29.16 8.339 31.05 8.429 ;
     RECT  2.304 8.24 2.898 8.465 ;
     RECT  27.684 8.429 28.314 8.465 ;
     RECT  5.076 8.311 8.73 8.477 ;
     RECT  5.076 8.477 6.93 8.501 ;
     RECT  29.16 8.429 29.898 8.501 ;
     RECT  0.216 8.237 0.234 8.525 ;
     RECT  2.415 8.465 2.862 8.525 ;
     RECT  6.48 8.501 6.93 8.525 ;
     RECT  2.415 8.525 2.826 8.537 ;
     RECT  5.076 8.501 5.094 8.537 ;
     RECT  6.48 8.525 6.498 8.537 ;
     RECT  7.815 8.477 8.73 8.537 ;
     RECT  28.044 8.465 28.314 8.537 ;
     RECT  31.032 8.429 31.05 8.537 ;
     RECT  7.815 8.537 8.01 8.573 ;
     RECT  17.928 8.429 18.705 8.609 ;
     RECT  28.296 8.537 28.314 8.609 ;
     RECT  2.415 8.537 2.505 8.657 ;
     RECT  7.815 8.573 7.905 8.657 ;
     RECT  13.215 8.387 13.305 8.657 ;
     RECT  18.615 8.609 18.705 8.657 ;
     RECT  24.015 8.387 24.105 8.657 ;
     RECT  29.415 8.501 29.505 8.657 ;
    LAYER M4 ;
     RECT  0.156 2.352 0.205 8.424 ;
     RECT  0.205 2.352 2.408 8.52 ;
     RECT  2.408 2.148 2.512 8.652 ;
     RECT  2.512 2.418 2.704 8.52 ;
     RECT  2.704 2.496 2.837 5.16 ;
     RECT  2.704 6.624 2.837 8.52 ;
     RECT  2.837 2.496 2.873 5.064 ;
     RECT  2.837 7.92 2.873 8.52 ;
     RECT  2.873 3.072 2.909 4.872 ;
     RECT  2.873 7.92 3.017 8.232 ;
     RECT  2.909 3.12 3.233 4.872 ;
     RECT  3.233 3.12 3.305 3.192 ;
     RECT  3.233 4.704 3.877 4.872 ;
     RECT  2.837 6.816 3.877 6.84 ;
     RECT  3.017 7.92 3.877 7.944 ;
     RECT  3.877 6.816 3.989 7.944 ;
     RECT  3.877 4.704 4.025 5.688 ;
     RECT  4.025 4.704 4.345 5.16 ;
     RECT  3.305 3.168 4.349 3.192 ;
     RECT  3.989 6.816 4.777 7.608 ;
     RECT  4.345 4.32 5.029 5.16 ;
     RECT  4.777 6.768 5.065 7.608 ;
     RECT  5.029 2.256 5.113 2.28 ;
     RECT  5.029 4.08 5.425 5.16 ;
     RECT  5.425 3.984 5.461 5.16 ;
     RECT  5.461 3.984 5.533 5.256 ;
     RECT  5.065 6.768 5.533 8.52 ;
     RECT  5.533 3.024 6.617 8.52 ;
     RECT  6.617 3.024 6.797 3.048 ;
     RECT  7.148 2.592 7.808 2.616 ;
     RECT  6.617 4.32 7.808 8.52 ;
     RECT  7.808 2.148 7.912 8.652 ;
     RECT  7.912 2.418 8.104 8.472 ;
     RECT  8.104 4.416 8.165 7.368 ;
     RECT  8.104 8.448 8.165 8.472 ;
     RECT  8.165 6.576 8.381 7.368 ;
     RECT  8.381 6.96 8.417 7.368 ;
     RECT  8.417 7.344 8.597 7.368 ;
     RECT  8.165 4.416 8.885 5.016 ;
     RECT  8.885 4.416 13.208 4.44 ;
     RECT  9.637 7.056 13.208 7.08 ;
     RECT  13.208 2.148 13.312 8.652 ;
     RECT  13.312 2.418 13.504 8.382 ;
     RECT  13.504 2.784 14.537 2.808 ;
     RECT  13.504 7.056 16.045 7.08 ;
     RECT  13.504 4.416 16.211 4.44 ;
     RECT  15.217 5.472 17.449 5.496 ;
     RECT  16.045 6.672 17.449 7.08 ;
     RECT  17.917 2.784 18.608 2.808 ;
     RECT  17.449 5.472 18.608 7.08 ;
     RECT  18.608 2.148 18.712 8.652 ;
     RECT  18.712 2.418 18.904 8.382 ;
     RECT  18.904 5.472 24.008 7.08 ;
     RECT  24.008 2.148 24.112 8.652 ;
     RECT  24.112 2.418 24.304 8.382 ;
     RECT  24.304 5.472 26.413 7.08 ;
     RECT  26.413 5.472 26.521 7.272 ;
     RECT  26.521 4.944 27.061 7.272 ;
     RECT  27.061 4.464 27.313 7.464 ;
     RECT  26.665 2.64 27.709 2.664 ;
     RECT  27.313 4.464 27.853 7.896 ;
     RECT  27.853 4.464 28.249 7.944 ;
     RECT  27.709 2.64 28.393 2.952 ;
     RECT  28.249 4.224 28.393 7.944 ;
     RECT  28.393 2.64 29.149 7.944 ;
     RECT  29.149 2.64 29.408 8.184 ;
     RECT  29.408 2.148 29.512 8.652 ;
     RECT  29.512 2.418 29.704 8.424 ;
     RECT  29.704 2.448 31.345 8.424 ;
     RECT  31.345 2.352 32.22 8.424 ;
    LAYER M5 ;
     RECT  2.4 2.137 2.52 2.151 ;
     RECT  7.8 2.137 7.92 2.151 ;
     RECT  13.2 2.137 13.32 2.151 ;
     RECT  18.6 2.137 18.72 2.151 ;
     RECT  24 2.137 24.12 2.151 ;
     RECT  29.4 2.137 29.52 2.151 ;
     RECT  7.8 2.151 8.112 2.581 ;
     RECT  0.336 3.733 0.36 3.923 ;
     RECT  2.4 2.151 2.712 4.261 ;
     RECT  7.2 2.581 8.112 4.309 ;
     RECT  2.4 4.261 2.808 5.171 ;
     RECT  5.04 2.245 5.064 5.171 ;
     RECT  6.96 4.309 8.112 5.555 ;
     RECT  2.4 5.171 2.712 6.661 ;
     RECT  2.4 6.661 2.808 7.571 ;
     RECT  7.2 5.555 8.112 8.051 ;
     RECT  2.4 7.571 2.712 8.649 ;
     RECT  7.8 8.051 8.112 8.649 ;
     RECT  13.2 2.151 13.512 8.649 ;
     RECT  18.6 2.151 18.912 8.649 ;
     RECT  24 2.151 24.312 8.649 ;
     RECT  29.4 2.151 29.712 8.649 ;
     RECT  2.4 8.649 2.52 8.663 ;
     RECT  7.8 8.649 7.92 8.663 ;
     RECT  13.2 8.649 13.32 8.663 ;
     RECT  18.6 8.649 18.72 8.663 ;
     RECT  24 8.649 24.12 8.663 ;
     RECT  29.4 8.649 29.52 8.663 ;
     RECT  2.712 5.171 2.808 6.661 ;
  END
END ot_qkh_head_nb_native
END LIBRARY
